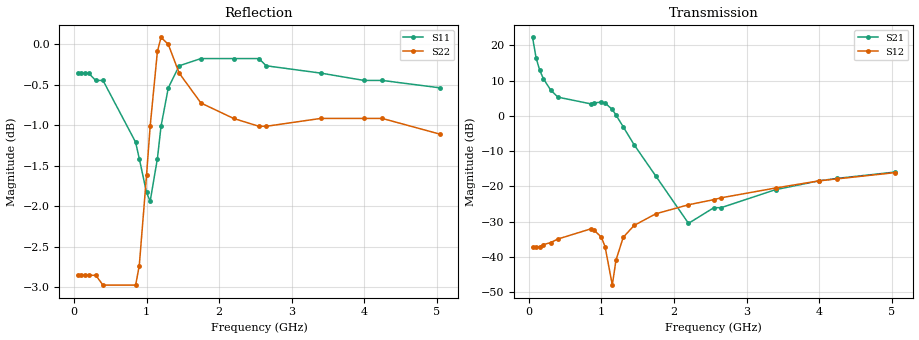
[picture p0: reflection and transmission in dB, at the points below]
!AT-36408
!S-PARAMETERS at Vce=3.6 V  Ic=150 mA.  LAST UPDATED 08-05-96
# ghz s ma r 50
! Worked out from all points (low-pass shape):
!   101 points, 50 MHz to 5.05 GHz, reference 50 ohm
!   highest |S21| = 22.23 dB at 50 MHz (marker M1); lowest = -30.5 dB at 2.2 GHz (marker M2)
!   |S21| within 3 dB of the highest: start of sweep to 75.36 MHz
!   lowest |S11| = -1.9 dB at 1.05 GHz (marker M3), VSWR 9.00, Z = 5.58 + j3.02 ohm
!   |S11| at or under -10 dB: nowhere
!   |S22| runs from -3.1 to 0.1 dB; largest |S21 - S12| = 13
!   S11 on the Smith chart (normalised r, x): 50 MHz: 0.02, -0.05; 850 MHz: 0.07, +0.10; 2.65 GHz: 0.02, +0.25; 4 GHz: 0.03, +0.43; 5.05 GHz: 0.04, +0.66
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0.05  0.96 -174.0  12.92 93.0  0.014 11.0  0.72 -168.0
0.1  0.96 -178.0  6.54 88.0  0.014 12.0  0.72 -174.0
0.15  0.96 -180.0  4.4 85.0  0.014 15.0  0.72 -175.0
0.2  0.96 179.0  3.35 82.0  0.015 17.0  0.72 -176.0
0.3  0.95 177.0  2.32 76.0  0.016 23.0  0.72 -176.0
0.4  0.95 175.0  1.84 71.0  0.018 26.0  0.71 -176.0
0.85  0.87 168.0  1.48 31.0  0.025 13.0  0.71 -166.0
0.9  0.85 168.0  1.52 22.0  0.024 6.0  0.73 -163.0
1  0.81 170.0  1.57 -1.0  0.019 -17.0  0.83 -160.0
1.05  0.8 173.0  1.52 -15.0  0.014 -34.0  0.89 -160.0
1.15  0.85 176.0  1.23 -44.0  0.004 -147.0  0.99 -165.0
1.2  0.89 176.0  1.03 -57.0  0.009 151.0  1.01 -169.0
1.3  0.94 174.0  0.7 -76.0  0.019 120.0  1 -173.0
1.45  0.97 171.0  0.39 -94.0  0.028 102.0  0.96 -176.0
1.75  0.98 165.0  0.14 -119.0  0.041 89.0  0.92 -178.0
2.2  0.98 158.0  0.03 170.0  0.055 81.0  0.9 -179.0
2.55  0.98 154.0  0.05 105.0  0.065 77.0  0.89 -179.0
2.65  0.97 152.0  0.05 97.0  0.069 77.0  0.89 -180.0
3.4  0.96 142.0  0.09 73.0  0.095 70.0  0.9 179.0
4  0.95 133.0  0.12 63.0  0.12 62.0  0.9 176.0
4.25  0.95 129.0  0.13 59.0  0.128 58.0  0.9 174.0
5.05  0.94 113.0  0.16 47.0  0.157 48.0  0.88 168.0
